# OpenTallas memory compiler (tools/mem_compiler), ASAP7 abstract view
VERSION 5.7 ;
BUSBITCHARS "[]" ;
DIVIDERCHAR "/" ;
PROPERTYDEFINITIONS
  MACRO width INTEGER ;
  MACRO depth INTEGER ;
  MACRO banks INTEGER ;
END PROPERTYDEFINITIONS
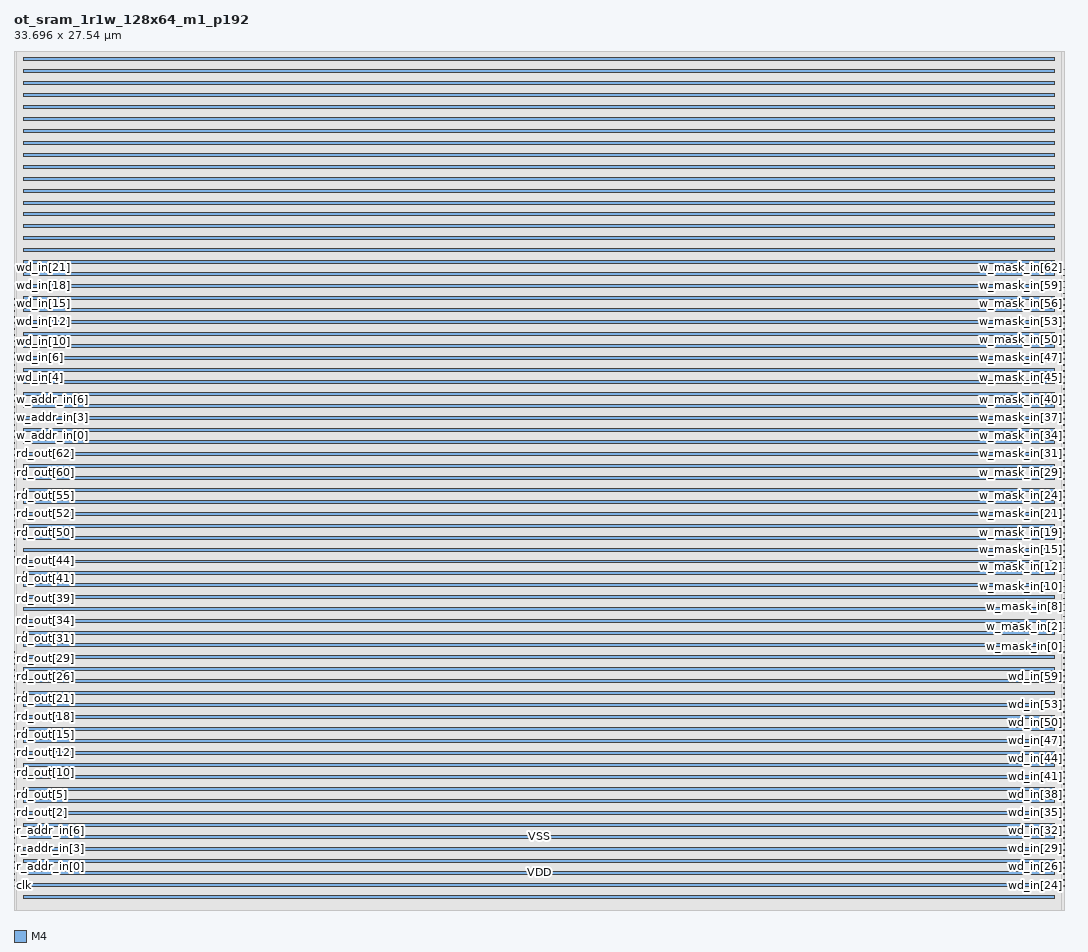
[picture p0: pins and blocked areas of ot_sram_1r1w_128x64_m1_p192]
MACRO ot_sram_1r1w_128x64_m1_p192
  PROPERTY width 64 ;
  PROPERTY depth 128 ;
  PROPERTY banks 1 ;
  FOREIGN ot_sram_1r1w_128x64_m1_p192 0 0 ;
  SYMMETRY X Y R90 ;
  SIZE 33.696 BY 27.540 ;
  CLASS BLOCK ;
  PIN clk
    DIRECTION INPUT ;
    USE CLOCK ;
    SHAPE ABUTMENT ;
    PORT
      LAYER M4 ;
      RECT 0.000 0.768 0.024 0.792 ;
    END
  END clk
  PIN r_ce_in
    DIRECTION INPUT ;
    USE SIGNAL ;
    SHAPE ABUTMENT ;
    PORT
      LAYER M4 ;
      RECT 0.000 0.960 0.024 0.984 ;
    END
  END r_ce_in
  PIN r_addr_in[0]
    DIRECTION INPUT ;
    USE SIGNAL ;
    SHAPE ABUTMENT ;
    PORT
      LAYER M4 ;
      RECT 0.000 1.152 0.024 1.176 ;
    END
  END r_addr_in[0]
  PIN r_addr_in[1]
    DIRECTION INPUT ;
    USE SIGNAL ;
    SHAPE ABUTMENT ;
    PORT
      LAYER M4 ;
      RECT 0.000 1.344 0.024 1.368 ;
    END
  END r_addr_in[1]
  PIN r_addr_in[2]
    DIRECTION INPUT ;
    USE SIGNAL ;
    SHAPE ABUTMENT ;
    PORT
      LAYER M4 ;
      RECT 0.000 1.536 0.024 1.560 ;
    END
  END r_addr_in[2]
  PIN r_addr_in[3]
    DIRECTION INPUT ;
    USE SIGNAL ;
    SHAPE ABUTMENT ;
    PORT
      LAYER M4 ;
      RECT 0.000 1.728 0.024 1.752 ;
    END
  END r_addr_in[3]
  PIN r_addr_in[4]
    DIRECTION INPUT ;
    USE SIGNAL ;
    SHAPE ABUTMENT ;
    PORT
      LAYER M4 ;
      RECT 0.000 1.920 0.024 1.944 ;
    END
  END r_addr_in[4]
  PIN r_addr_in[5]
    DIRECTION INPUT ;
    USE SIGNAL ;
    SHAPE ABUTMENT ;
    PORT
      LAYER M4 ;
      RECT 0.000 2.112 0.024 2.136 ;
    END
  END r_addr_in[5]
  PIN r_addr_in[6]
    DIRECTION INPUT ;
    USE SIGNAL ;
    SHAPE ABUTMENT ;
    PORT
      LAYER M4 ;
      RECT 0.000 2.304 0.024 2.328 ;
    END
  END r_addr_in[6]
  PIN rd_out[0]
    DIRECTION OUTPUT ;
    USE SIGNAL ;
    SHAPE ABUTMENT ;
    PORT
      LAYER M4 ;
      RECT 0.000 2.496 0.024 2.520 ;
    END
  END rd_out[0]
  PIN rd_out[1]
    DIRECTION OUTPUT ;
    USE SIGNAL ;
    SHAPE ABUTMENT ;
    PORT
      LAYER M4 ;
      RECT 0.000 2.688 0.024 2.712 ;
    END
  END rd_out[1]
  PIN rd_out[2]
    DIRECTION OUTPUT ;
    USE SIGNAL ;
    SHAPE ABUTMENT ;
    PORT
      LAYER M4 ;
      RECT 0.000 2.880 0.024 2.904 ;
    END
  END rd_out[2]
  PIN rd_out[3]
    DIRECTION OUTPUT ;
    USE SIGNAL ;
    SHAPE ABUTMENT ;
    PORT
      LAYER M4 ;
      RECT 0.000 3.072 0.024 3.096 ;
    END
  END rd_out[3]
  PIN rd_out[4]
    DIRECTION OUTPUT ;
    USE SIGNAL ;
    SHAPE ABUTMENT ;
    PORT
      LAYER M4 ;
      RECT 0.000 3.264 0.024 3.288 ;
    END
  END rd_out[4]
  PIN rd_out[5]
    DIRECTION OUTPUT ;
    USE SIGNAL ;
    SHAPE ABUTMENT ;
    PORT
      LAYER M4 ;
      RECT 0.000 3.456 0.024 3.480 ;
    END
  END rd_out[5]
  PIN rd_out[6]
    DIRECTION OUTPUT ;
    USE SIGNAL ;
    SHAPE ABUTMENT ;
    PORT
      LAYER M4 ;
      RECT 0.000 3.648 0.024 3.672 ;
    END
  END rd_out[6]
  PIN rd_out[7]
    DIRECTION OUTPUT ;
    USE SIGNAL ;
    SHAPE ABUTMENT ;
    PORT
      LAYER M4 ;
      RECT 0.000 3.840 0.024 3.864 ;
    END
  END rd_out[7]
  PIN rd_out[8]
    DIRECTION OUTPUT ;
    USE SIGNAL ;
    SHAPE ABUTMENT ;
    PORT
      LAYER M4 ;
      RECT 0.000 4.032 0.024 4.056 ;
    END
  END rd_out[8]
  PIN rd_out[9]
    DIRECTION OUTPUT ;
    USE SIGNAL ;
    SHAPE ABUTMENT ;
    PORT
      LAYER M4 ;
      RECT 0.000 4.224 0.024 4.248 ;
    END
  END rd_out[9]
  PIN rd_out[10]
    DIRECTION OUTPUT ;
    USE SIGNAL ;
    SHAPE ABUTMENT ;
    PORT
      LAYER M4 ;
      RECT 0.000 4.416 0.024 4.440 ;
    END
  END rd_out[10]
  PIN rd_out[11]
    DIRECTION OUTPUT ;
    USE SIGNAL ;
    SHAPE ABUTMENT ;
    PORT
      LAYER M4 ;
      RECT 0.000 4.608 0.024 4.632 ;
    END
  END rd_out[11]
  PIN rd_out[12]
    DIRECTION OUTPUT ;
    USE SIGNAL ;
    SHAPE ABUTMENT ;
    PORT
      LAYER M4 ;
      RECT 0.000 4.800 0.024 4.824 ;
    END
  END rd_out[12]
  PIN rd_out[13]
    DIRECTION OUTPUT ;
    USE SIGNAL ;
    SHAPE ABUTMENT ;
    PORT
      LAYER M4 ;
      RECT 0.000 4.992 0.024 5.016 ;
    END
  END rd_out[13]
  PIN rd_out[14]
    DIRECTION OUTPUT ;
    USE SIGNAL ;
    SHAPE ABUTMENT ;
    PORT
      LAYER M4 ;
      RECT 0.000 5.184 0.024 5.208 ;
    END
  END rd_out[14]
  PIN rd_out[15]
    DIRECTION OUTPUT ;
    USE SIGNAL ;
    SHAPE ABUTMENT ;
    PORT
      LAYER M4 ;
      RECT 0.000 5.376 0.024 5.400 ;
    END
  END rd_out[15]
  PIN rd_out[16]
    DIRECTION OUTPUT ;
    USE SIGNAL ;
    SHAPE ABUTMENT ;
    PORT
      LAYER M4 ;
      RECT 0.000 5.568 0.024 5.592 ;
    END
  END rd_out[16]
  PIN rd_out[17]
    DIRECTION OUTPUT ;
    USE SIGNAL ;
    SHAPE ABUTMENT ;
    PORT
      LAYER M4 ;
      RECT 0.000 5.760 0.024 5.784 ;
    END
  END rd_out[17]
  PIN rd_out[18]
    DIRECTION OUTPUT ;
    USE SIGNAL ;
    SHAPE ABUTMENT ;
    PORT
      LAYER M4 ;
      RECT 0.000 5.952 0.024 5.976 ;
    END
  END rd_out[18]
  PIN rd_out[19]
    DIRECTION OUTPUT ;
    USE SIGNAL ;
    SHAPE ABUTMENT ;
    PORT
      LAYER M4 ;
      RECT 0.000 6.144 0.024 6.168 ;
    END
  END rd_out[19]
  PIN rd_out[20]
    DIRECTION OUTPUT ;
    USE SIGNAL ;
    SHAPE ABUTMENT ;
    PORT
      LAYER M4 ;
      RECT 0.000 6.336 0.024 6.360 ;
    END
  END rd_out[20]
  PIN rd_out[21]
    DIRECTION OUTPUT ;
    USE SIGNAL ;
    SHAPE ABUTMENT ;
    PORT
      LAYER M4 ;
      RECT 0.000 6.528 0.024 6.552 ;
    END
  END rd_out[21]
  PIN rd_out[22]
    DIRECTION OUTPUT ;
    USE SIGNAL ;
    SHAPE ABUTMENT ;
    PORT
      LAYER M4 ;
      RECT 0.000 6.720 0.024 6.744 ;
    END
  END rd_out[22]
  PIN rd_out[23]
    DIRECTION OUTPUT ;
    USE SIGNAL ;
    SHAPE ABUTMENT ;
    PORT
      LAYER M4 ;
      RECT 0.000 6.912 0.024 6.936 ;
    END
  END rd_out[23]
  PIN rd_out[24]
    DIRECTION OUTPUT ;
    USE SIGNAL ;
    SHAPE ABUTMENT ;
    PORT
      LAYER M4 ;
      RECT 0.000 7.104 0.024 7.128 ;
    END
  END rd_out[24]
  PIN rd_out[25]
    DIRECTION OUTPUT ;
    USE SIGNAL ;
    SHAPE ABUTMENT ;
    PORT
      LAYER M4 ;
      RECT 0.000 7.296 0.024 7.320 ;
    END
  END rd_out[25]
  PIN rd_out[26]
    DIRECTION OUTPUT ;
    USE SIGNAL ;
    SHAPE ABUTMENT ;
    PORT
      LAYER M4 ;
      RECT 0.000 7.488 0.024 7.512 ;
    END
  END rd_out[26]
  PIN rd_out[27]
    DIRECTION OUTPUT ;
    USE SIGNAL ;
    SHAPE ABUTMENT ;
    PORT
      LAYER M4 ;
      RECT 0.000 7.680 0.024 7.704 ;
    END
  END rd_out[27]
  PIN rd_out[28]
    DIRECTION OUTPUT ;
    USE SIGNAL ;
    SHAPE ABUTMENT ;
    PORT
      LAYER M4 ;
      RECT 0.000 7.872 0.024 7.896 ;
    END
  END rd_out[28]
  PIN rd_out[29]
    DIRECTION OUTPUT ;
    USE SIGNAL ;
    SHAPE ABUTMENT ;
    PORT
      LAYER M4 ;
      RECT 0.000 8.064 0.024 8.088 ;
    END
  END rd_out[29]
  PIN rd_out[30]
    DIRECTION OUTPUT ;
    USE SIGNAL ;
    SHAPE ABUTMENT ;
    PORT
      LAYER M4 ;
      RECT 0.000 8.256 0.024 8.280 ;
    END
  END rd_out[30]
  PIN rd_out[31]
    DIRECTION OUTPUT ;
    USE SIGNAL ;
    SHAPE ABUTMENT ;
    PORT
      LAYER M4 ;
      RECT 0.000 8.448 0.024 8.472 ;
    END
  END rd_out[31]
  PIN rd_out[32]
    DIRECTION OUTPUT ;
    USE SIGNAL ;
    SHAPE ABUTMENT ;
    PORT
      LAYER M4 ;
      RECT 0.000 8.640 0.024 8.664 ;
    END
  END rd_out[32]
  PIN rd_out[33]
    DIRECTION OUTPUT ;
    USE SIGNAL ;
    SHAPE ABUTMENT ;
    PORT
      LAYER M4 ;
      RECT 0.000 8.832 0.024 8.856 ;
    END
  END rd_out[33]
  PIN rd_out[34]
    DIRECTION OUTPUT ;
    USE SIGNAL ;
    SHAPE ABUTMENT ;
    PORT
      LAYER M4 ;
      RECT 0.000 9.024 0.024 9.048 ;
    END
  END rd_out[34]
  PIN rd_out[35]
    DIRECTION OUTPUT ;
    USE SIGNAL ;
    SHAPE ABUTMENT ;
    PORT
      LAYER M4 ;
      RECT 0.000 9.216 0.024 9.240 ;
    END
  END rd_out[35]
  PIN rd_out[36]
    DIRECTION OUTPUT ;
    USE SIGNAL ;
    SHAPE ABUTMENT ;
    PORT
      LAYER M4 ;
      RECT 0.000 9.408 0.024 9.432 ;
    END
  END rd_out[36]
  PIN rd_out[37]
    DIRECTION OUTPUT ;
    USE SIGNAL ;
    SHAPE ABUTMENT ;
    PORT
      LAYER M4 ;
      RECT 0.000 9.600 0.024 9.624 ;
    END
  END rd_out[37]
  PIN rd_out[38]
    DIRECTION OUTPUT ;
    USE SIGNAL ;
    SHAPE ABUTMENT ;
    PORT
      LAYER M4 ;
      RECT 0.000 9.792 0.024 9.816 ;
    END
  END rd_out[38]
  PIN rd_out[39]
    DIRECTION OUTPUT ;
    USE SIGNAL ;
    SHAPE ABUTMENT ;
    PORT
      LAYER M4 ;
      RECT 0.000 9.984 0.024 10.008 ;
    END
  END rd_out[39]
  PIN rd_out[40]
    DIRECTION OUTPUT ;
    USE SIGNAL ;
    SHAPE ABUTMENT ;
    PORT
      LAYER M4 ;
      RECT 0.000 10.176 0.024 10.200 ;
    END
  END rd_out[40]
  PIN rd_out[41]
    DIRECTION OUTPUT ;
    USE SIGNAL ;
    SHAPE ABUTMENT ;
    PORT
      LAYER M4 ;
      RECT 0.000 10.368 0.024 10.392 ;
    END
  END rd_out[41]
  PIN rd_out[42]
    DIRECTION OUTPUT ;
    USE SIGNAL ;
    SHAPE ABUTMENT ;
    PORT
      LAYER M4 ;
      RECT 0.000 10.560 0.024 10.584 ;
    END
  END rd_out[42]
  PIN rd_out[43]
    DIRECTION OUTPUT ;
    USE SIGNAL ;
    SHAPE ABUTMENT ;
    PORT
      LAYER M4 ;
      RECT 0.000 10.752 0.024 10.776 ;
    END
  END rd_out[43]
  PIN rd_out[44]
    DIRECTION OUTPUT ;
    USE SIGNAL ;
    SHAPE ABUTMENT ;
    PORT
      LAYER M4 ;
      RECT 0.000 10.944 0.024 10.968 ;
    END
  END rd_out[44]
  PIN rd_out[45]
    DIRECTION OUTPUT ;
    USE SIGNAL ;
    SHAPE ABUTMENT ;
    PORT
      LAYER M4 ;
      RECT 0.000 11.136 0.024 11.160 ;
    END
  END rd_out[45]
  PIN rd_out[46]
    DIRECTION OUTPUT ;
    USE SIGNAL ;
    SHAPE ABUTMENT ;
    PORT
      LAYER M4 ;
      RECT 0.000 11.328 0.024 11.352 ;
    END
  END rd_out[46]
  PIN rd_out[47]
    DIRECTION OUTPUT ;
    USE SIGNAL ;
    SHAPE ABUTMENT ;
    PORT
      LAYER M4 ;
      RECT 0.000 11.520 0.024 11.544 ;
    END
  END rd_out[47]
  PIN rd_out[48]
    DIRECTION OUTPUT ;
    USE SIGNAL ;
    SHAPE ABUTMENT ;
    PORT
      LAYER M4 ;
      RECT 0.000 11.712 0.024 11.736 ;
    END
  END rd_out[48]
  PIN rd_out[49]
    DIRECTION OUTPUT ;
    USE SIGNAL ;
    SHAPE ABUTMENT ;
    PORT
      LAYER M4 ;
      RECT 0.000 11.904 0.024 11.928 ;
    END
  END rd_out[49]
  PIN rd_out[50]
    DIRECTION OUTPUT ;
    USE SIGNAL ;
    SHAPE ABUTMENT ;
    PORT
      LAYER M4 ;
      RECT 0.000 12.096 0.024 12.120 ;
    END
  END rd_out[50]
  PIN rd_out[51]
    DIRECTION OUTPUT ;
    USE SIGNAL ;
    SHAPE ABUTMENT ;
    PORT
      LAYER M4 ;
      RECT 0.000 12.288 0.024 12.312 ;
    END
  END rd_out[51]
  PIN rd_out[52]
    DIRECTION OUTPUT ;
    USE SIGNAL ;
    SHAPE ABUTMENT ;
    PORT
      LAYER M4 ;
      RECT 0.000 12.480 0.024 12.504 ;
    END
  END rd_out[52]
  PIN rd_out[53]
    DIRECTION OUTPUT ;
    USE SIGNAL ;
    SHAPE ABUTMENT ;
    PORT
      LAYER M4 ;
      RECT 0.000 12.672 0.024 12.696 ;
    END
  END rd_out[53]
  PIN rd_out[54]
    DIRECTION OUTPUT ;
    USE SIGNAL ;
    SHAPE ABUTMENT ;
    PORT
      LAYER M4 ;
      RECT 0.000 12.864 0.024 12.888 ;
    END
  END rd_out[54]
  PIN rd_out[55]
    DIRECTION OUTPUT ;
    USE SIGNAL ;
    SHAPE ABUTMENT ;
    PORT
      LAYER M4 ;
      RECT 0.000 13.056 0.024 13.080 ;
    END
  END rd_out[55]
  PIN rd_out[56]
    DIRECTION OUTPUT ;
    USE SIGNAL ;
    SHAPE ABUTMENT ;
    PORT
      LAYER M4 ;
      RECT 0.000 13.248 0.024 13.272 ;
    END
  END rd_out[56]
  PIN rd_out[57]
    DIRECTION OUTPUT ;
    USE SIGNAL ;
    SHAPE ABUTMENT ;
    PORT
      LAYER M4 ;
      RECT 0.000 13.440 0.024 13.464 ;
    END
  END rd_out[57]
  PIN rd_out[58]
    DIRECTION OUTPUT ;
    USE SIGNAL ;
    SHAPE ABUTMENT ;
    PORT
      LAYER M4 ;
      RECT 0.000 13.632 0.024 13.656 ;
    END
  END rd_out[58]
  PIN rd_out[59]
    DIRECTION OUTPUT ;
    USE SIGNAL ;
    SHAPE ABUTMENT ;
    PORT
      LAYER M4 ;
      RECT 0.000 13.824 0.024 13.848 ;
    END
  END rd_out[59]
  PIN rd_out[60]
    DIRECTION OUTPUT ;
    USE SIGNAL ;
    SHAPE ABUTMENT ;
    PORT
      LAYER M4 ;
      RECT 0.000 14.016 0.024 14.040 ;
    END
  END rd_out[60]
  PIN rd_out[61]
    DIRECTION OUTPUT ;
    USE SIGNAL ;
    SHAPE ABUTMENT ;
    PORT
      LAYER M4 ;
      RECT 0.000 14.208 0.024 14.232 ;
    END
  END rd_out[61]
  PIN rd_out[62]
    DIRECTION OUTPUT ;
    USE SIGNAL ;
    SHAPE ABUTMENT ;
    PORT
      LAYER M4 ;
      RECT 0.000 14.400 0.024 14.424 ;
    END
  END rd_out[62]
  PIN rd_out[63]
    DIRECTION OUTPUT ;
    USE SIGNAL ;
    SHAPE ABUTMENT ;
    PORT
      LAYER M4 ;
      RECT 0.000 14.592 0.024 14.616 ;
    END
  END rd_out[63]
  PIN w_ce_in
    DIRECTION INPUT ;
    USE SIGNAL ;
    SHAPE ABUTMENT ;
    PORT
      LAYER M4 ;
      RECT 0.000 14.784 0.024 14.808 ;
    END
  END w_ce_in
  PIN w_addr_in[0]
    DIRECTION INPUT ;
    USE SIGNAL ;
    SHAPE ABUTMENT ;
    PORT
      LAYER M4 ;
      RECT 0.000 14.976 0.024 15.000 ;
    END
  END w_addr_in[0]
  PIN w_addr_in[1]
    DIRECTION INPUT ;
    USE SIGNAL ;
    SHAPE ABUTMENT ;
    PORT
      LAYER M4 ;
      RECT 0.000 15.168 0.024 15.192 ;
    END
  END w_addr_in[1]
  PIN w_addr_in[2]
    DIRECTION INPUT ;
    USE SIGNAL ;
    SHAPE ABUTMENT ;
    PORT
      LAYER M4 ;
      RECT 0.000 15.360 0.024 15.384 ;
    END
  END w_addr_in[2]
  PIN w_addr_in[3]
    DIRECTION INPUT ;
    USE SIGNAL ;
    SHAPE ABUTMENT ;
    PORT
      LAYER M4 ;
      RECT 0.000 15.552 0.024 15.576 ;
    END
  END w_addr_in[3]
  PIN w_addr_in[4]
    DIRECTION INPUT ;
    USE SIGNAL ;
    SHAPE ABUTMENT ;
    PORT
      LAYER M4 ;
      RECT 0.000 15.744 0.024 15.768 ;
    END
  END w_addr_in[4]
  PIN w_addr_in[5]
    DIRECTION INPUT ;
    USE SIGNAL ;
    SHAPE ABUTMENT ;
    PORT
      LAYER M4 ;
      RECT 0.000 15.936 0.024 15.960 ;
    END
  END w_addr_in[5]
  PIN w_addr_in[6]
    DIRECTION INPUT ;
    USE SIGNAL ;
    SHAPE ABUTMENT ;
    PORT
      LAYER M4 ;
      RECT 0.000 16.128 0.024 16.152 ;
    END
  END w_addr_in[6]
  PIN wd_in[0]
    DIRECTION INPUT ;
    USE SIGNAL ;
    SHAPE ABUTMENT ;
    PORT
      LAYER M4 ;
      RECT 0.000 16.320 0.024 16.344 ;
    END
  END wd_in[0]
  PIN wd_in[1]
    DIRECTION INPUT ;
    USE SIGNAL ;
    SHAPE ABUTMENT ;
    PORT
      LAYER M4 ;
      RECT 0.000 16.512 0.024 16.536 ;
    END
  END wd_in[1]
  PIN wd_in[2]
    DIRECTION INPUT ;
    USE SIGNAL ;
    SHAPE ABUTMENT ;
    PORT
      LAYER M4 ;
      RECT 0.000 16.704 0.024 16.728 ;
    END
  END wd_in[2]
  PIN wd_in[3]
    DIRECTION INPUT ;
    USE SIGNAL ;
    SHAPE ABUTMENT ;
    PORT
      LAYER M4 ;
      RECT 0.000 16.896 0.024 16.920 ;
    END
  END wd_in[3]
  PIN wd_in[4]
    DIRECTION INPUT ;
    USE SIGNAL ;
    SHAPE ABUTMENT ;
    PORT
      LAYER M4 ;
      RECT 0.000 17.088 0.024 17.112 ;
    END
  END wd_in[4]
  PIN wd_in[5]
    DIRECTION INPUT ;
    USE SIGNAL ;
    SHAPE ABUTMENT ;
    PORT
      LAYER M4 ;
      RECT 0.000 17.280 0.024 17.304 ;
    END
  END wd_in[5]
  PIN wd_in[6]
    DIRECTION INPUT ;
    USE SIGNAL ;
    SHAPE ABUTMENT ;
    PORT
      LAYER M4 ;
      RECT 0.000 17.472 0.024 17.496 ;
    END
  END wd_in[6]
  PIN wd_in[7]
    DIRECTION INPUT ;
    USE SIGNAL ;
    SHAPE ABUTMENT ;
    PORT
      LAYER M4 ;
      RECT 0.000 17.664 0.024 17.688 ;
    END
  END wd_in[7]
  PIN wd_in[8]
    DIRECTION INPUT ;
    USE SIGNAL ;
    SHAPE ABUTMENT ;
    PORT
      LAYER M4 ;
      RECT 0.000 17.856 0.024 17.880 ;
    END
  END wd_in[8]
  PIN wd_in[9]
    DIRECTION INPUT ;
    USE SIGNAL ;
    SHAPE ABUTMENT ;
    PORT
      LAYER M4 ;
      RECT 0.000 18.048 0.024 18.072 ;
    END
  END wd_in[9]
  PIN wd_in[10]
    DIRECTION INPUT ;
    USE SIGNAL ;
    SHAPE ABUTMENT ;
    PORT
      LAYER M4 ;
      RECT 0.000 18.240 0.024 18.264 ;
    END
  END wd_in[10]
  PIN wd_in[11]
    DIRECTION INPUT ;
    USE SIGNAL ;
    SHAPE ABUTMENT ;
    PORT
      LAYER M4 ;
      RECT 0.000 18.432 0.024 18.456 ;
    END
  END wd_in[11]
  PIN wd_in[12]
    DIRECTION INPUT ;
    USE SIGNAL ;
    SHAPE ABUTMENT ;
    PORT
      LAYER M4 ;
      RECT 0.000 18.624 0.024 18.648 ;
    END
  END wd_in[12]
  PIN wd_in[13]
    DIRECTION INPUT ;
    USE SIGNAL ;
    SHAPE ABUTMENT ;
    PORT
      LAYER M4 ;
      RECT 0.000 18.816 0.024 18.840 ;
    END
  END wd_in[13]
  PIN wd_in[14]
    DIRECTION INPUT ;
    USE SIGNAL ;
    SHAPE ABUTMENT ;
    PORT
      LAYER M4 ;
      RECT 0.000 19.008 0.024 19.032 ;
    END
  END wd_in[14]
  PIN wd_in[15]
    DIRECTION INPUT ;
    USE SIGNAL ;
    SHAPE ABUTMENT ;
    PORT
      LAYER M4 ;
      RECT 0.000 19.200 0.024 19.224 ;
    END
  END wd_in[15]
  PIN wd_in[16]
    DIRECTION INPUT ;
    USE SIGNAL ;
    SHAPE ABUTMENT ;
    PORT
      LAYER M4 ;
      RECT 0.000 19.392 0.024 19.416 ;
    END
  END wd_in[16]
  PIN wd_in[17]
    DIRECTION INPUT ;
    USE SIGNAL ;
    SHAPE ABUTMENT ;
    PORT
      LAYER M4 ;
      RECT 0.000 19.584 0.024 19.608 ;
    END
  END wd_in[17]
  PIN wd_in[18]
    DIRECTION INPUT ;
    USE SIGNAL ;
    SHAPE ABUTMENT ;
    PORT
      LAYER M4 ;
      RECT 0.000 19.776 0.024 19.800 ;
    END
  END wd_in[18]
  PIN wd_in[19]
    DIRECTION INPUT ;
    USE SIGNAL ;
    SHAPE ABUTMENT ;
    PORT
      LAYER M4 ;
      RECT 0.000 19.968 0.024 19.992 ;
    END
  END wd_in[19]
  PIN wd_in[20]
    DIRECTION INPUT ;
    USE SIGNAL ;
    SHAPE ABUTMENT ;
    PORT
      LAYER M4 ;
      RECT 0.000 20.160 0.024 20.184 ;
    END
  END wd_in[20]
  PIN wd_in[21]
    DIRECTION INPUT ;
    USE SIGNAL ;
    SHAPE ABUTMENT ;
    PORT
      LAYER M4 ;
      RECT 0.000 20.352 0.024 20.376 ;
    END
  END wd_in[21]
  PIN wd_in[22]
    DIRECTION INPUT ;
    USE SIGNAL ;
    SHAPE ABUTMENT ;
    PORT
      LAYER M4 ;
      RECT 0.000 20.544 0.024 20.568 ;
    END
  END wd_in[22]
  PIN wd_in[23]
    DIRECTION INPUT ;
    USE SIGNAL ;
    SHAPE ABUTMENT ;
    PORT
      LAYER M4 ;
      RECT 0.000 20.736 0.024 20.760 ;
    END
  END wd_in[23]
  PIN wd_in[24]
    DIRECTION INPUT ;
    USE SIGNAL ;
    SHAPE ABUTMENT ;
    PORT
      LAYER M4 ;
      RECT 33.672 0.768 33.696 0.792 ;
    END
  END wd_in[24]
  PIN wd_in[25]
    DIRECTION INPUT ;
    USE SIGNAL ;
    SHAPE ABUTMENT ;
    PORT
      LAYER M4 ;
      RECT 33.672 0.960 33.696 0.984 ;
    END
  END wd_in[25]
  PIN wd_in[26]
    DIRECTION INPUT ;
    USE SIGNAL ;
    SHAPE ABUTMENT ;
    PORT
      LAYER M4 ;
      RECT 33.672 1.152 33.696 1.176 ;
    END
  END wd_in[26]
  PIN wd_in[27]
    DIRECTION INPUT ;
    USE SIGNAL ;
    SHAPE ABUTMENT ;
    PORT
      LAYER M4 ;
      RECT 33.672 1.344 33.696 1.368 ;
    END
  END wd_in[27]
  PIN wd_in[28]
    DIRECTION INPUT ;
    USE SIGNAL ;
    SHAPE ABUTMENT ;
    PORT
      LAYER M4 ;
      RECT 33.672 1.536 33.696 1.560 ;
    END
  END wd_in[28]
  PIN wd_in[29]
    DIRECTION INPUT ;
    USE SIGNAL ;
    SHAPE ABUTMENT ;
    PORT
      LAYER M4 ;
      RECT 33.672 1.728 33.696 1.752 ;
    END
  END wd_in[29]
  PIN wd_in[30]
    DIRECTION INPUT ;
    USE SIGNAL ;
    SHAPE ABUTMENT ;
    PORT
      LAYER M4 ;
      RECT 33.672 1.920 33.696 1.944 ;
    END
  END wd_in[30]
  PIN wd_in[31]
    DIRECTION INPUT ;
    USE SIGNAL ;
    SHAPE ABUTMENT ;
    PORT
      LAYER M4 ;
      RECT 33.672 2.112 33.696 2.136 ;
    END
  END wd_in[31]
  PIN wd_in[32]
    DIRECTION INPUT ;
    USE SIGNAL ;
    SHAPE ABUTMENT ;
    PORT
      LAYER M4 ;
      RECT 33.672 2.304 33.696 2.328 ;
    END
  END wd_in[32]
  PIN wd_in[33]
    DIRECTION INPUT ;
    USE SIGNAL ;
    SHAPE ABUTMENT ;
    PORT
      LAYER M4 ;
      RECT 33.672 2.496 33.696 2.520 ;
    END
  END wd_in[33]
  PIN wd_in[34]
    DIRECTION INPUT ;
    USE SIGNAL ;
    SHAPE ABUTMENT ;
    PORT
      LAYER M4 ;
      RECT 33.672 2.688 33.696 2.712 ;
    END
  END wd_in[34]
  PIN wd_in[35]
    DIRECTION INPUT ;
    USE SIGNAL ;
    SHAPE ABUTMENT ;
    PORT
      LAYER M4 ;
      RECT 33.672 2.880 33.696 2.904 ;
    END
  END wd_in[35]
  PIN wd_in[36]
    DIRECTION INPUT ;
    USE SIGNAL ;
    SHAPE ABUTMENT ;
    PORT
      LAYER M4 ;
      RECT 33.672 3.072 33.696 3.096 ;
    END
  END wd_in[36]
  PIN wd_in[37]
    DIRECTION INPUT ;
    USE SIGNAL ;
    SHAPE ABUTMENT ;
    PORT
      LAYER M4 ;
      RECT 33.672 3.264 33.696 3.288 ;
    END
  END wd_in[37]
  PIN wd_in[38]
    DIRECTION INPUT ;
    USE SIGNAL ;
    SHAPE ABUTMENT ;
    PORT
      LAYER M4 ;
      RECT 33.672 3.456 33.696 3.480 ;
    END
  END wd_in[38]
  PIN wd_in[39]
    DIRECTION INPUT ;
    USE SIGNAL ;
    SHAPE ABUTMENT ;
    PORT
      LAYER M4 ;
      RECT 33.672 3.648 33.696 3.672 ;
    END
  END wd_in[39]
  PIN wd_in[40]
    DIRECTION INPUT ;
    USE SIGNAL ;
    SHAPE ABUTMENT ;
    PORT
      LAYER M4 ;
      RECT 33.672 3.840 33.696 3.864 ;
    END
  END wd_in[40]
  PIN wd_in[41]
    DIRECTION INPUT ;
    USE SIGNAL ;
    SHAPE ABUTMENT ;
    PORT
      LAYER M4 ;
      RECT 33.672 4.032 33.696 4.056 ;
    END
  END wd_in[41]
  PIN wd_in[42]
    DIRECTION INPUT ;
    USE SIGNAL ;
    SHAPE ABUTMENT ;
    PORT
      LAYER M4 ;
      RECT 33.672 4.224 33.696 4.248 ;
    END
  END wd_in[42]
  PIN wd_in[43]
    DIRECTION INPUT ;
    USE SIGNAL ;
    SHAPE ABUTMENT ;
    PORT
      LAYER M4 ;
      RECT 33.672 4.416 33.696 4.440 ;
    END
  END wd_in[43]
  PIN wd_in[44]
    DIRECTION INPUT ;
    USE SIGNAL ;
    SHAPE ABUTMENT ;
    PORT
      LAYER M4 ;
      RECT 33.672 4.608 33.696 4.632 ;
    END
  END wd_in[44]
  PIN wd_in[45]
    DIRECTION INPUT ;
    USE SIGNAL ;
    SHAPE ABUTMENT ;
    PORT
      LAYER M4 ;
      RECT 33.672 4.800 33.696 4.824 ;
    END
  END wd_in[45]
  PIN wd_in[46]
    DIRECTION INPUT ;
    USE SIGNAL ;
    SHAPE ABUTMENT ;
    PORT
      LAYER M4 ;
      RECT 33.672 4.992 33.696 5.016 ;
    END
  END wd_in[46]
  PIN wd_in[47]
    DIRECTION INPUT ;
    USE SIGNAL ;
    SHAPE ABUTMENT ;
    PORT
      LAYER M4 ;
      RECT 33.672 5.184 33.696 5.208 ;
    END
  END wd_in[47]
  PIN wd_in[48]
    DIRECTION INPUT ;
    USE SIGNAL ;
    SHAPE ABUTMENT ;
    PORT
      LAYER M4 ;
      RECT 33.672 5.376 33.696 5.400 ;
    END
  END wd_in[48]
  PIN wd_in[49]
    DIRECTION INPUT ;
    USE SIGNAL ;
    SHAPE ABUTMENT ;
    PORT
      LAYER M4 ;
      RECT 33.672 5.568 33.696 5.592 ;
    END
  END wd_in[49]
  PIN wd_in[50]
    DIRECTION INPUT ;
    USE SIGNAL ;
    SHAPE ABUTMENT ;
    PORT
      LAYER M4 ;
      RECT 33.672 5.760 33.696 5.784 ;
    END
  END wd_in[50]
  PIN wd_in[51]
    DIRECTION INPUT ;
    USE SIGNAL ;
    SHAPE ABUTMENT ;
    PORT
      LAYER M4 ;
      RECT 33.672 5.952 33.696 5.976 ;
    END
  END wd_in[51]
  PIN wd_in[52]
    DIRECTION INPUT ;
    USE SIGNAL ;
    SHAPE ABUTMENT ;
    PORT
      LAYER M4 ;
      RECT 33.672 6.144 33.696 6.168 ;
    END
  END wd_in[52]
  PIN wd_in[53]
    DIRECTION INPUT ;
    USE SIGNAL ;
    SHAPE ABUTMENT ;
    PORT
      LAYER M4 ;
      RECT 33.672 6.336 33.696 6.360 ;
    END
  END wd_in[53]
  PIN wd_in[54]
    DIRECTION INPUT ;
    USE SIGNAL ;
    SHAPE ABUTMENT ;
    PORT
      LAYER M4 ;
      RECT 33.672 6.528 33.696 6.552 ;
    END
  END wd_in[54]
  PIN wd_in[55]
    DIRECTION INPUT ;
    USE SIGNAL ;
    SHAPE ABUTMENT ;
    PORT
      LAYER M4 ;
      RECT 33.672 6.720 33.696 6.744 ;
    END
  END wd_in[55]
  PIN wd_in[56]
    DIRECTION INPUT ;
    USE SIGNAL ;
    SHAPE ABUTMENT ;
    PORT
      LAYER M4 ;
      RECT 33.672 6.912 33.696 6.936 ;
    END
  END wd_in[56]
  PIN wd_in[57]
    DIRECTION INPUT ;
    USE SIGNAL ;
    SHAPE ABUTMENT ;
    PORT
      LAYER M4 ;
      RECT 33.672 7.104 33.696 7.128 ;
    END
  END wd_in[57]
  PIN wd_in[58]
    DIRECTION INPUT ;
    USE SIGNAL ;
    SHAPE ABUTMENT ;
    PORT
      LAYER M4 ;
      RECT 33.672 7.296 33.696 7.320 ;
    END
  END wd_in[58]
  PIN wd_in[59]
    DIRECTION INPUT ;
    USE SIGNAL ;
    SHAPE ABUTMENT ;
    PORT
      LAYER M4 ;
      RECT 33.672 7.488 33.696 7.512 ;
    END
  END wd_in[59]
  PIN wd_in[60]
    DIRECTION INPUT ;
    USE SIGNAL ;
    SHAPE ABUTMENT ;
    PORT
      LAYER M4 ;
      RECT 33.672 7.680 33.696 7.704 ;
    END
  END wd_in[60]
  PIN wd_in[61]
    DIRECTION INPUT ;
    USE SIGNAL ;
    SHAPE ABUTMENT ;
    PORT
      LAYER M4 ;
      RECT 33.672 7.872 33.696 7.896 ;
    END
  END wd_in[61]
  PIN wd_in[62]
    DIRECTION INPUT ;
    USE SIGNAL ;
    SHAPE ABUTMENT ;
    PORT
      LAYER M4 ;
      RECT 33.672 8.064 33.696 8.088 ;
    END
  END wd_in[62]
  PIN wd_in[63]
    DIRECTION INPUT ;
    USE SIGNAL ;
    SHAPE ABUTMENT ;
    PORT
      LAYER M4 ;
      RECT 33.672 8.256 33.696 8.280 ;
    END
  END wd_in[63]
  PIN w_mask_in[0]
    DIRECTION INPUT ;
    USE SIGNAL ;
    SHAPE ABUTMENT ;
    PORT
      LAYER M4 ;
      RECT 33.672 8.448 33.696 8.472 ;
    END
  END w_mask_in[0]
  PIN w_mask_in[1]
    DIRECTION INPUT ;
    USE SIGNAL ;
    SHAPE ABUTMENT ;
    PORT
      LAYER M4 ;
      RECT 33.672 8.640 33.696 8.664 ;
    END
  END w_mask_in[1]
  PIN w_mask_in[2]
    DIRECTION INPUT ;
    USE SIGNAL ;
    SHAPE ABUTMENT ;
    PORT
      LAYER M4 ;
      RECT 33.672 8.832 33.696 8.856 ;
    END
  END w_mask_in[2]
  PIN w_mask_in[3]
    DIRECTION INPUT ;
    USE SIGNAL ;
    SHAPE ABUTMENT ;
    PORT
      LAYER M4 ;
      RECT 33.672 9.024 33.696 9.048 ;
    END
  END w_mask_in[3]
  PIN w_mask_in[4]
    DIRECTION INPUT ;
    USE SIGNAL ;
    SHAPE ABUTMENT ;
    PORT
      LAYER M4 ;
      RECT 33.672 9.216 33.696 9.240 ;
    END
  END w_mask_in[4]
  PIN w_mask_in[5]
    DIRECTION INPUT ;
    USE SIGNAL ;
    SHAPE ABUTMENT ;
    PORT
      LAYER M4 ;
      RECT 33.672 9.408 33.696 9.432 ;
    END
  END w_mask_in[5]
  PIN w_mask_in[6]
    DIRECTION INPUT ;
    USE SIGNAL ;
    SHAPE ABUTMENT ;
    PORT
      LAYER M4 ;
      RECT 33.672 9.600 33.696 9.624 ;
    END
  END w_mask_in[6]
  PIN w_mask_in[7]
    DIRECTION INPUT ;
    USE SIGNAL ;
    SHAPE ABUTMENT ;
    PORT
      LAYER M4 ;
      RECT 33.672 9.792 33.696 9.816 ;
    END
  END w_mask_in[7]
  PIN w_mask_in[8]
    DIRECTION INPUT ;
    USE SIGNAL ;
    SHAPE ABUTMENT ;
    PORT
      LAYER M4 ;
      RECT 33.672 9.984 33.696 10.008 ;
    END
  END w_mask_in[8]
  PIN w_mask_in[9]
    DIRECTION INPUT ;
    USE SIGNAL ;
    SHAPE ABUTMENT ;
    PORT
      LAYER M4 ;
      RECT 33.672 10.176 33.696 10.200 ;
    END
  END w_mask_in[9]
  PIN w_mask_in[10]
    DIRECTION INPUT ;
    USE SIGNAL ;
    SHAPE ABUTMENT ;
    PORT
      LAYER M4 ;
      RECT 33.672 10.368 33.696 10.392 ;
    END
  END w_mask_in[10]
  PIN w_mask_in[11]
    DIRECTION INPUT ;
    USE SIGNAL ;
    SHAPE ABUTMENT ;
    PORT
      LAYER M4 ;
      RECT 33.672 10.560 33.696 10.584 ;
    END
  END w_mask_in[11]
  PIN w_mask_in[12]
    DIRECTION INPUT ;
    USE SIGNAL ;
    SHAPE ABUTMENT ;
    PORT
      LAYER M4 ;
      RECT 33.672 10.752 33.696 10.776 ;
    END
  END w_mask_in[12]
  PIN w_mask_in[13]
    DIRECTION INPUT ;
    USE SIGNAL ;
    SHAPE ABUTMENT ;
    PORT
      LAYER M4 ;
      RECT 33.672 10.944 33.696 10.968 ;
    END
  END w_mask_in[13]
  PIN w_mask_in[14]
    DIRECTION INPUT ;
    USE SIGNAL ;
    SHAPE ABUTMENT ;
    PORT
      LAYER M4 ;
      RECT 33.672 11.136 33.696 11.160 ;
    END
  END w_mask_in[14]
  PIN w_mask_in[15]
    DIRECTION INPUT ;
    USE SIGNAL ;
    SHAPE ABUTMENT ;
    PORT
      LAYER M4 ;
      RECT 33.672 11.328 33.696 11.352 ;
    END
  END w_mask_in[15]
  PIN w_mask_in[16]
    DIRECTION INPUT ;
    USE SIGNAL ;
    SHAPE ABUTMENT ;
    PORT
      LAYER M4 ;
      RECT 33.672 11.520 33.696 11.544 ;
    END
  END w_mask_in[16]
  PIN w_mask_in[17]
    DIRECTION INPUT ;
    USE SIGNAL ;
    SHAPE ABUTMENT ;
    PORT
      LAYER M4 ;
      RECT 33.672 11.712 33.696 11.736 ;
    END
  END w_mask_in[17]
  PIN w_mask_in[18]
    DIRECTION INPUT ;
    USE SIGNAL ;
    SHAPE ABUTMENT ;
    PORT
      LAYER M4 ;
      RECT 33.672 11.904 33.696 11.928 ;
    END
  END w_mask_in[18]
  PIN w_mask_in[19]
    DIRECTION INPUT ;
    USE SIGNAL ;
    SHAPE ABUTMENT ;
    PORT
      LAYER M4 ;
      RECT 33.672 12.096 33.696 12.120 ;
    END
  END w_mask_in[19]
  PIN w_mask_in[20]
    DIRECTION INPUT ;
    USE SIGNAL ;
    SHAPE ABUTMENT ;
    PORT
      LAYER M4 ;
      RECT 33.672 12.288 33.696 12.312 ;
    END
  END w_mask_in[20]
  PIN w_mask_in[21]
    DIRECTION INPUT ;
    USE SIGNAL ;
    SHAPE ABUTMENT ;
    PORT
      LAYER M4 ;
      RECT 33.672 12.480 33.696 12.504 ;
    END
  END w_mask_in[21]
  PIN w_mask_in[22]
    DIRECTION INPUT ;
    USE SIGNAL ;
    SHAPE ABUTMENT ;
    PORT
      LAYER M4 ;
      RECT 33.672 12.672 33.696 12.696 ;
    END
  END w_mask_in[22]
  PIN w_mask_in[23]
    DIRECTION INPUT ;
    USE SIGNAL ;
    SHAPE ABUTMENT ;
    PORT
      LAYER M4 ;
      RECT 33.672 12.864 33.696 12.888 ;
    END
  END w_mask_in[23]
  PIN w_mask_in[24]
    DIRECTION INPUT ;
    USE SIGNAL ;
    SHAPE ABUTMENT ;
    PORT
      LAYER M4 ;
      RECT 33.672 13.056 33.696 13.080 ;
    END
  END w_mask_in[24]
  PIN w_mask_in[25]
    DIRECTION INPUT ;
    USE SIGNAL ;
    SHAPE ABUTMENT ;
    PORT
      LAYER M4 ;
      RECT 33.672 13.248 33.696 13.272 ;
    END
  END w_mask_in[25]
  PIN w_mask_in[26]
    DIRECTION INPUT ;
    USE SIGNAL ;
    SHAPE ABUTMENT ;
    PORT
      LAYER M4 ;
      RECT 33.672 13.440 33.696 13.464 ;
    END
  END w_mask_in[26]
  PIN w_mask_in[27]
    DIRECTION INPUT ;
    USE SIGNAL ;
    SHAPE ABUTMENT ;
    PORT
      LAYER M4 ;
      RECT 33.672 13.632 33.696 13.656 ;
    END
  END w_mask_in[27]
  PIN w_mask_in[28]
    DIRECTION INPUT ;
    USE SIGNAL ;
    SHAPE ABUTMENT ;
    PORT
      LAYER M4 ;
      RECT 33.672 13.824 33.696 13.848 ;
    END
  END w_mask_in[28]
  PIN w_mask_in[29]
    DIRECTION INPUT ;
    USE SIGNAL ;
    SHAPE ABUTMENT ;
    PORT
      LAYER M4 ;
      RECT 33.672 14.016 33.696 14.040 ;
    END
  END w_mask_in[29]
  PIN w_mask_in[30]
    DIRECTION INPUT ;
    USE SIGNAL ;
    SHAPE ABUTMENT ;
    PORT
      LAYER M4 ;
      RECT 33.672 14.208 33.696 14.232 ;
    END
  END w_mask_in[30]
  PIN w_mask_in[31]
    DIRECTION INPUT ;
    USE SIGNAL ;
    SHAPE ABUTMENT ;
    PORT
      LAYER M4 ;
      RECT 33.672 14.400 33.696 14.424 ;
    END
  END w_mask_in[31]
  PIN w_mask_in[32]
    DIRECTION INPUT ;
    USE SIGNAL ;
    SHAPE ABUTMENT ;
    PORT
      LAYER M4 ;
      RECT 33.672 14.592 33.696 14.616 ;
    END
  END w_mask_in[32]
  PIN w_mask_in[33]
    DIRECTION INPUT ;
    USE SIGNAL ;
    SHAPE ABUTMENT ;
    PORT
      LAYER M4 ;
      RECT 33.672 14.784 33.696 14.808 ;
    END
  END w_mask_in[33]
  PIN w_mask_in[34]
    DIRECTION INPUT ;
    USE SIGNAL ;
    SHAPE ABUTMENT ;
    PORT
      LAYER M4 ;
      RECT 33.672 14.976 33.696 15.000 ;
    END
  END w_mask_in[34]
  PIN w_mask_in[35]
    DIRECTION INPUT ;
    USE SIGNAL ;
    SHAPE ABUTMENT ;
    PORT
      LAYER M4 ;
      RECT 33.672 15.168 33.696 15.192 ;
    END
  END w_mask_in[35]
  PIN w_mask_in[36]
    DIRECTION INPUT ;
    USE SIGNAL ;
    SHAPE ABUTMENT ;
    PORT
      LAYER M4 ;
      RECT 33.672 15.360 33.696 15.384 ;
    END
  END w_mask_in[36]
  PIN w_mask_in[37]
    DIRECTION INPUT ;
    USE SIGNAL ;
    SHAPE ABUTMENT ;
    PORT
      LAYER M4 ;
      RECT 33.672 15.552 33.696 15.576 ;
    END
  END w_mask_in[37]
  PIN w_mask_in[38]
    DIRECTION INPUT ;
    USE SIGNAL ;
    SHAPE ABUTMENT ;
    PORT
      LAYER M4 ;
      RECT 33.672 15.744 33.696 15.768 ;
    END
  END w_mask_in[38]
  PIN w_mask_in[39]
    DIRECTION INPUT ;
    USE SIGNAL ;
    SHAPE ABUTMENT ;
    PORT
      LAYER M4 ;
      RECT 33.672 15.936 33.696 15.960 ;
    END
  END w_mask_in[39]
  PIN w_mask_in[40]
    DIRECTION INPUT ;
    USE SIGNAL ;
    SHAPE ABUTMENT ;
    PORT
      LAYER M4 ;
      RECT 33.672 16.128 33.696 16.152 ;
    END
  END w_mask_in[40]
  PIN w_mask_in[41]
    DIRECTION INPUT ;
    USE SIGNAL ;
    SHAPE ABUTMENT ;
    PORT
      LAYER M4 ;
      RECT 33.672 16.320 33.696 16.344 ;
    END
  END w_mask_in[41]
  PIN w_mask_in[42]
    DIRECTION INPUT ;
    USE SIGNAL ;
    SHAPE ABUTMENT ;
    PORT
      LAYER M4 ;
      RECT 33.672 16.512 33.696 16.536 ;
    END
  END w_mask_in[42]
  PIN w_mask_in[43]
    DIRECTION INPUT ;
    USE SIGNAL ;
    SHAPE ABUTMENT ;
    PORT
      LAYER M4 ;
      RECT 33.672 16.704 33.696 16.728 ;
    END
  END w_mask_in[43]
  PIN w_mask_in[44]
    DIRECTION INPUT ;
    USE SIGNAL ;
    SHAPE ABUTMENT ;
    PORT
      LAYER M4 ;
      RECT 33.672 16.896 33.696 16.920 ;
    END
  END w_mask_in[44]
  PIN w_mask_in[45]
    DIRECTION INPUT ;
    USE SIGNAL ;
    SHAPE ABUTMENT ;
    PORT
      LAYER M4 ;
      RECT 33.672 17.088 33.696 17.112 ;
    END
  END w_mask_in[45]
  PIN w_mask_in[46]
    DIRECTION INPUT ;
    USE SIGNAL ;
    SHAPE ABUTMENT ;
    PORT
      LAYER M4 ;
      RECT 33.672 17.280 33.696 17.304 ;
    END
  END w_mask_in[46]
  PIN w_mask_in[47]
    DIRECTION INPUT ;
    USE SIGNAL ;
    SHAPE ABUTMENT ;
    PORT
      LAYER M4 ;
      RECT 33.672 17.472 33.696 17.496 ;
    END
  END w_mask_in[47]
  PIN w_mask_in[48]
    DIRECTION INPUT ;
    USE SIGNAL ;
    SHAPE ABUTMENT ;
    PORT
      LAYER M4 ;
      RECT 33.672 17.664 33.696 17.688 ;
    END
  END w_mask_in[48]
  PIN w_mask_in[49]
    DIRECTION INPUT ;
    USE SIGNAL ;
    SHAPE ABUTMENT ;
    PORT
      LAYER M4 ;
      RECT 33.672 17.856 33.696 17.880 ;
    END
  END w_mask_in[49]
  PIN w_mask_in[50]
    DIRECTION INPUT ;
    USE SIGNAL ;
    SHAPE ABUTMENT ;
    PORT
      LAYER M4 ;
      RECT 33.672 18.048 33.696 18.072 ;
    END
  END w_mask_in[50]
  PIN w_mask_in[51]
    DIRECTION INPUT ;
    USE SIGNAL ;
    SHAPE ABUTMENT ;
    PORT
      LAYER M4 ;
      RECT 33.672 18.240 33.696 18.264 ;
    END
  END w_mask_in[51]
  PIN w_mask_in[52]
    DIRECTION INPUT ;
    USE SIGNAL ;
    SHAPE ABUTMENT ;
    PORT
      LAYER M4 ;
      RECT 33.672 18.432 33.696 18.456 ;
    END
  END w_mask_in[52]
  PIN w_mask_in[53]
    DIRECTION INPUT ;
    USE SIGNAL ;
    SHAPE ABUTMENT ;
    PORT
      LAYER M4 ;
      RECT 33.672 18.624 33.696 18.648 ;
    END
  END w_mask_in[53]
  PIN w_mask_in[54]
    DIRECTION INPUT ;
    USE SIGNAL ;
    SHAPE ABUTMENT ;
    PORT
      LAYER M4 ;
      RECT 33.672 18.816 33.696 18.840 ;
    END
  END w_mask_in[54]
  PIN w_mask_in[55]
    DIRECTION INPUT ;
    USE SIGNAL ;
    SHAPE ABUTMENT ;
    PORT
      LAYER M4 ;
      RECT 33.672 19.008 33.696 19.032 ;
    END
  END w_mask_in[55]
  PIN w_mask_in[56]
    DIRECTION INPUT ;
    USE SIGNAL ;
    SHAPE ABUTMENT ;
    PORT
      LAYER M4 ;
      RECT 33.672 19.200 33.696 19.224 ;
    END
  END w_mask_in[56]
  PIN w_mask_in[57]
    DIRECTION INPUT ;
    USE SIGNAL ;
    SHAPE ABUTMENT ;
    PORT
      LAYER M4 ;
      RECT 33.672 19.392 33.696 19.416 ;
    END
  END w_mask_in[57]
  PIN w_mask_in[58]
    DIRECTION INPUT ;
    USE SIGNAL ;
    SHAPE ABUTMENT ;
    PORT
      LAYER M4 ;
      RECT 33.672 19.584 33.696 19.608 ;
    END
  END w_mask_in[58]
  PIN w_mask_in[59]
    DIRECTION INPUT ;
    USE SIGNAL ;
    SHAPE ABUTMENT ;
    PORT
      LAYER M4 ;
      RECT 33.672 19.776 33.696 19.800 ;
    END
  END w_mask_in[59]
  PIN w_mask_in[60]
    DIRECTION INPUT ;
    USE SIGNAL ;
    SHAPE ABUTMENT ;
    PORT
      LAYER M4 ;
      RECT 33.672 19.968 33.696 19.992 ;
    END
  END w_mask_in[60]
  PIN w_mask_in[61]
    DIRECTION INPUT ;
    USE SIGNAL ;
    SHAPE ABUTMENT ;
    PORT
      LAYER M4 ;
      RECT 33.672 20.160 33.696 20.184 ;
    END
  END w_mask_in[61]
  PIN w_mask_in[62]
    DIRECTION INPUT ;
    USE SIGNAL ;
    SHAPE ABUTMENT ;
    PORT
      LAYER M4 ;
      RECT 33.672 20.352 33.696 20.376 ;
    END
  END w_mask_in[62]
  PIN w_mask_in[63]
    DIRECTION INPUT ;
    USE SIGNAL ;
    SHAPE ABUTMENT ;
    PORT
      LAYER M4 ;
      RECT 33.672 20.544 33.696 20.568 ;
    END
  END w_mask_in[63]
  PIN VDD
    DIRECTION INOUT ;
    USE POWER ;
    PORT
      LAYER M4 ;
      RECT 0.300 0.384 33.396 0.480 ;
      RECT 0.300 1.152 33.396 1.248 ;
      RECT 0.300 1.920 33.396 2.016 ;
      RECT 0.300 2.688 33.396 2.784 ;
      RECT 0.300 3.456 33.396 3.552 ;
      RECT 0.300 4.224 33.396 4.320 ;
      RECT 0.300 4.992 33.396 5.088 ;
      RECT 0.300 5.760 33.396 5.856 ;
      RECT 0.300 6.528 33.396 6.624 ;
      RECT 0.300 7.296 33.396 7.392 ;
      RECT 0.300 8.064 33.396 8.160 ;
      RECT 0.300 8.832 33.396 8.928 ;
      RECT 0.300 9.600 33.396 9.696 ;
      RECT 0.300 10.368 33.396 10.464 ;
      RECT 0.300 11.136 33.396 11.232 ;
      RECT 0.300 11.904 33.396 12.000 ;
      RECT 0.300 12.672 33.396 12.768 ;
      RECT 0.300 13.440 33.396 13.536 ;
      RECT 0.300 14.208 33.396 14.304 ;
      RECT 0.300 14.976 33.396 15.072 ;
      RECT 0.300 15.744 33.396 15.840 ;
      RECT 0.300 16.512 33.396 16.608 ;
      RECT 0.300 17.280 33.396 17.376 ;
      RECT 0.300 18.048 33.396 18.144 ;
      RECT 0.300 18.816 33.396 18.912 ;
      RECT 0.300 19.584 33.396 19.680 ;
      RECT 0.300 20.352 33.396 20.448 ;
      RECT 0.300 21.120 33.396 21.216 ;
      RECT 0.300 21.888 33.396 21.984 ;
      RECT 0.300 22.656 33.396 22.752 ;
      RECT 0.300 23.424 33.396 23.520 ;
      RECT 0.300 24.192 33.396 24.288 ;
      RECT 0.300 24.960 33.396 25.056 ;
      RECT 0.300 25.728 33.396 25.824 ;
      RECT 0.300 26.496 33.396 26.592 ;
      RECT 0.300 27.264 33.396 27.360 ;
    END
  END VDD
  PIN VSS
    DIRECTION INOUT ;
    USE GROUND ;
    PORT
      LAYER M4 ;
      RECT 0.300 0.768 33.396 0.864 ;
      RECT 0.300 1.536 33.396 1.632 ;
      RECT 0.300 2.304 33.396 2.400 ;
      RECT 0.300 3.072 33.396 3.168 ;
      RECT 0.300 3.840 33.396 3.936 ;
      RECT 0.300 4.608 33.396 4.704 ;
      RECT 0.300 5.376 33.396 5.472 ;
      RECT 0.300 6.144 33.396 6.240 ;
      RECT 0.300 6.912 33.396 7.008 ;
      RECT 0.300 7.680 33.396 7.776 ;
      RECT 0.300 8.448 33.396 8.544 ;
      RECT 0.300 9.216 33.396 9.312 ;
      RECT 0.300 9.984 33.396 10.080 ;
      RECT 0.300 10.752 33.396 10.848 ;
      RECT 0.300 11.520 33.396 11.616 ;
      RECT 0.300 12.288 33.396 12.384 ;
      RECT 0.300 13.056 33.396 13.152 ;
      RECT 0.300 13.824 33.396 13.920 ;
      RECT 0.300 14.592 33.396 14.688 ;
      RECT 0.300 15.360 33.396 15.456 ;
      RECT 0.300 16.128 33.396 16.224 ;
      RECT 0.300 16.896 33.396 16.992 ;
      RECT 0.300 17.664 33.396 17.760 ;
      RECT 0.300 18.432 33.396 18.528 ;
      RECT 0.300 19.200 33.396 19.296 ;
      RECT 0.300 19.968 33.396 20.064 ;
      RECT 0.300 20.736 33.396 20.832 ;
      RECT 0.300 21.504 33.396 21.600 ;
      RECT 0.300 22.272 33.396 22.368 ;
      RECT 0.300 23.040 33.396 23.136 ;
      RECT 0.300 23.808 33.396 23.904 ;
      RECT 0.300 24.576 33.396 24.672 ;
      RECT 0.300 25.344 33.396 25.440 ;
      RECT 0.300 26.112 33.396 26.208 ;
      RECT 0.300 26.880 33.396 26.976 ;
    END
  END VSS
  OBS
    LAYER M1 ;
    RECT 0 0 33.696 27.540 ;
    LAYER M2 ;
    RECT 0 0 33.696 27.540 ;
    LAYER M3 ;
    RECT 0 0 33.696 27.540 ;
    LAYER M4 ;
    RECT 0.072 0 33.624 27.540 ;
  END
END ot_sram_1r1w_128x64_m1_p192

END LIBRARY
